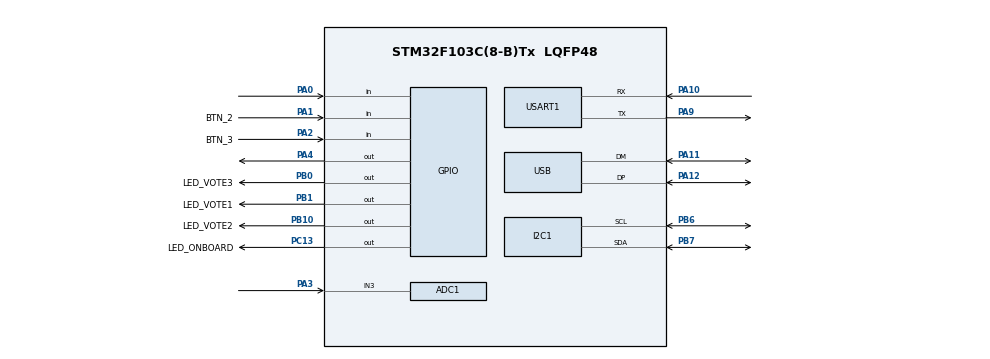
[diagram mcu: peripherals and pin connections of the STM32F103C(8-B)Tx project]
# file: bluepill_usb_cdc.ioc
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ADC1.Channel-0\#ChannelRegularConversion=ADC_CHANNEL_3
ADC1.ContinuousConvMode=ENABLE
ADC1.EnableInjectedConversion=ENABLE
ADC1.NbrOfConversionFlag=1
ADC1.Rank-0\#ChannelRegularConversion=1
ADC1.SamplingTime-0\#ChannelRegularConversion=ADC_SAMPLETIME_1CYCLE_5
ADC1.master=1
FREERTOS.BinarySemaphores01=ConfirmSem,Dynamic,NULL,Available
FREERTOS.Queues01=VoteQueue,5,8,1,Dynamic,NULL,NULL
FREERTOS.Tasks01=defaultTask,24,128,StartDefaultTask,Default,NULL,Dynamic,NULL,NULL;VoteInterface,41,256,StartVoteTask,Default,NULL,Dynamic,NULL,NULL;CommManager,24,256,StartCommTask,Default,NULL,Dynamic,NULL,NULL
FREERTOS.configTOTAL_HEAP_SIZE=8192
Mcu.Family=STM32F1
Mcu.Name=STM32F103C(8-B)Tx
Mcu.Package=LQFP48
NVIC.PriorityGroup=NVIC_PRIORITYGROUP_4
NVIC.USB_LP_CAN1_RX0_IRQn=true\:5\:0\:false\:false\:true\:true\:false\:true\:true
PA0-WKUP.Signal=GPIO_Input
PA1.GPIO_Label=BTN_2
PA1.GPIO_PuPd=GPIO_PULLUP
PA1.Signal=GPIO_Input
PA10.Mode=Asynchronous
PA10.Signal=USART1_RX
PA11.Mode=Device
PA11.Signal=USB_DM
PA12.Mode=Device
PA12.Signal=USB_DP
PA13.Mode=Serial_Wire
PA13.Signal=SYS_JTMS-SWDIO
PA14.Mode=Serial_Wire
PA14.Signal=SYS_JTCK-SWCLK
PA2.GPIO_Label=BTN_3
PA2.GPIO_PuPd=GPIO_PULLUP
PA2.Signal=GPIO_Input
PA3.Signal=ADCx_IN3
PA4.Signal=GPIO_Output
PA9.Mode=Asynchronous
PA9.Signal=USART1_TX
PB0.GPIO_Label=LED_VOTE3
PB0.Signal=GPIO_Output
PB1.GPIO_Label=LED_VOTE1
PB1.Signal=GPIO_Output
PB10.GPIO_Label=LED_VOTE2
PB10.Signal=GPIO_Output
PB6.Mode=I2C
PB6.Signal=I2C1_SCL
PB7.Mode=I2C
PB7.Signal=I2C1_SDA
PC13-TAMPER-RTC.GPIO_Label=LED_ONBOARD
PC13-TAMPER-RTC.Signal=GPIO_Output
PD0-OSC_IN.Mode=HSE-External-Oscillator
PD0-OSC_IN.Signal=RCC_OSC_IN
PD1-OSC_OUT.Mode=HSE-External-Oscillator
PD1-OSC_OUT.Signal=RCC_OSC_OUT
ProjectManager.HeapSize=0x200
ProjectManager.StackSize=0x400
ProjectManager.TargetToolchain=STM32CubeIDE
RCC.AHBFreq_Value=72000000
RCC.APB1CLKDivider=RCC_HCLK_DIV2
RCC.APB1Freq_Value=36000000
RCC.APB1TimFreq_Value=72000000
RCC.APB2Freq_Value=72000000
RCC.APB2TimFreq_Value=72000000
RCC.HCLKFreq_Value=72000000
RCC.PLLMUL=RCC_PLL_MUL9
RCC.PLLSourceVirtual=RCC_PLLSOURCE_HSE
RCC.SYSCLKFreq_VALUE=72000000
RCC.SYSCLKSource=RCC_SYSCLKSOURCE_PLLCLK
RCC.USBFreq_Value=72000000
SH.ADCx_IN3.0=ADC1_IN3,IN3
USART1.VirtualMode=VM_ASYNC
USB_DEVICE.CLASS_NAME_FS=CDC
USB_DEVICE.VirtualMode=Cdc
USB_DEVICE.VirtualModeFS=Cdc_FS
VP_FREERTOS_VS_CMSIS_V2.Mode=CMSIS_V2
VP_USB_DEVICE_VS_USB_DEVICE_CDC_FS.Mode=CDC_FS
board=custom

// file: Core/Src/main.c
/* USER CODE BEGIN Header */
/**
******************************************************************************
* @file           : main.c
* @brief          : Main program body - UART + ADC TEST (Blue Pill FAKE SAFE)
******************************************************************************
* @attention
*
* Copyright (c) 2025 STMicroelectronics.
* All rights reserved.
*
* This software is licensed under terms that can be found in the LICENSE file
* in the root directory of this software component.
* If no LICENSE file comes with this software, it is provided AS-IS.
******************************************************************************
*/
/* USER CODE END Header */

#include "main.h"
#include "cmsis_os.h"
#include "adc.h"
#include "i2c.h"
#include "usart.h"
// #include "usb_device.h"   // ❌ SCOS – NU folosim USB pe Blue Pill fake
#include "gpio.h"
#include <stdio.h>
#include <string.h>

/* USER CODE BEGIN PV */
char msg[50];
int Timeout = 1000;
uint32_t LDR_raw = 0;
/* USER CODE END PV */

void SystemClock_Config(void);
void MX_FREERTOS_Init(void);

int main(void)
{

  /* MCU Configuration--------------------------------------------------------*/
  HAL_Init();

  /* Configure the system clock */
  SystemClock_Config();

  /* Initialize all configured peripherals */
  MX_GPIO_Init();
  MX_I2C1_Init();
  MX_USART1_UART_Init();
  MX_ADC1_Init();

  /* USER CODE BEGIN 2 */

  // ========================================
  // ★★★ TEST LED ONBOARD PC13 ★★★
  // ========================================
  HAL_GPIO_WritePin(GPIOC, GPIO_PIN_13, GPIO_PIN_RESET); // LED ON
  HAL_Delay(2000);

  for(int i = 0; i < 10; i++) {
    HAL_GPIO_TogglePin(GPIOC, GPIO_PIN_13);
    HAL_Delay(200);
  }

  HAL_GPIO_WritePin(GPIOC, GPIO_PIN_13, GPIO_PIN_SET); // LED OFF

  // TEST UART
  HAL_UART_Transmit(&huart1,
      (uint8_t*)"=== UART + ADC TEST START ===\r\n",
      32,
      1000);

  HAL_Delay(1000);
  // ========================================

  /* USER CODE END 2 */

  /* FreeRTOS – dezactivat pentru test bare-metal */
  // osKernelInitialize();
  // MX_FREERTOS_Init();
  // osKernelStart();

  /* Infinite loop */
  while (1)
  {

    /* USER CODE BEGIN 3 */

    // ADC Polling + UART Transmit
    if (HAL_ADC_Start(&hadc1) == HAL_OK)
    {
      if (HAL_ADC_PollForConversion(&hadc1, Timeout) == HAL_OK)
      {
        LDR_raw = HAL_ADC_GetValue(&hadc1);

        int len = sprintf(msg, "LDR raw data: %lu\r\n", LDR_raw);
        HAL_UART_Transmit(&huart1, (uint8_t*)msg, len, 1000);
      }
      HAL_ADC_Stop(&hadc1);
    }

    HAL_Delay(1000); // 1 secunda
  }
  /* USER CODE END 3 */
}

void SystemClock_Config(void)
{
  RCC_OscInitTypeDef RCC_OscInitStruct = {0};
  RCC_ClkInitTypeDef RCC_ClkInitStruct = {0};

  // ===============================
  // ★ CLOCK INTERN – HSI ★
  // ===============================
  RCC_OscInitStruct.OscillatorType = RCC_OSCILLATORTYPE_HSI;
  RCC_OscInitStruct.HSIState = RCC_HSI_ON;
  RCC_OscInitStruct.HSICalibrationValue = RCC_HSICALIBRATION_DEFAULT;
  RCC_OscInitStruct.PLL.PLLState = RCC_PLL_ON;
  RCC_OscInitStruct.PLL.PLLSource = RCC_PLLSOURCE_HSI_DIV2;
  RCC_OscInitStruct.PLL.PLLMUL = RCC_PLL_MUL16; // 64 MHz

  if (HAL_RCC_OscConfig(&RCC_OscInitStruct) != HAL_OK)
  {
    Error_Handler();
  }

  RCC_ClkInitStruct.ClockType =
      RCC_CLOCKTYPE_HCLK |
      RCC_CLOCKTYPE_SYSCLK |
      RCC_CLOCKTYPE_PCLK1 |
      RCC_CLOCKTYPE_PCLK2;

  RCC_ClkInitStruct.SYSCLKSource = RCC_SYSCLKSOURCE_PLLCLK;
  RCC_ClkInitStruct.AHBCLKDivider = RCC_SYSCLK_DIV1;
  RCC_ClkInitStruct.APB1CLKDivider = RCC_HCLK_DIV2;
  RCC_ClkInitStruct.APB2CLKDivider = RCC_HCLK_DIV1;

  if (HAL_RCC_ClockConfig(&RCC_ClkInitStruct, FLASH_LATENCY_2) != HAL_OK)
  {
    Error_Handler();
  }
}

/**
  * @brief  Error Handler
  * @retval None
  */
void Error_Handler(void)
{
  __disable_irq();
  while (1)
  {
  }
}
